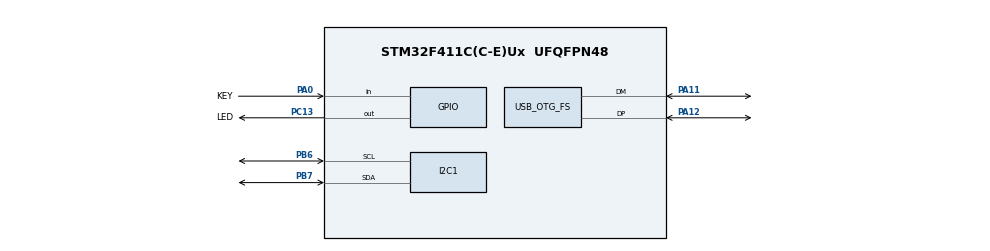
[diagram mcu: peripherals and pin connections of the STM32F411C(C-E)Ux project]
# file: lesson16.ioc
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Mcu.Family=STM32F4
Mcu.Name=STM32F411C(C-E)Ux
Mcu.Package=UFQFPN48
NVIC.OTG_FS_IRQn=true\:0\:0\:false\:false\:true\:false\:true\:true
NVIC.PriorityGroup=NVIC_PRIORITYGROUP_4
PA0-WKUP.GPIO_Label=KEY
PA0-WKUP.GPIO_PuPd=GPIO_PULLUP
PA0-WKUP.Signal=GPIO_Input
PA11.Mode=Device_Only
PA11.Signal=USB_OTG_FS_DM
PA12.Mode=Device_Only
PA12.Signal=USB_OTG_FS_DP
PA13.Mode=Serial_Wire
PA13.Signal=SYS_JTMS-SWDIO
PA14.Mode=Serial_Wire
PA14.Signal=SYS_JTCK-SWCLK
PB6.Mode=I2C
PB6.Signal=I2C1_SCL
PB7.Mode=I2C
PB7.Signal=I2C1_SDA
PC13-ANTI_TAMP.GPIO_Label=LED
PC13-ANTI_TAMP.PinState=GPIO_PIN_SET
PC13-ANTI_TAMP.Signal=GPIO_Output
PH0\ -\ OSC_IN.Mode=HSE-External-Oscillator
PH0\ -\ OSC_IN.Signal=RCC_OSC_IN
PH1\ -\ OSC_OUT.Mode=HSE-External-Oscillator
PH1\ -\ OSC_OUT.Signal=RCC_OSC_OUT
ProjectManager.HeapSize=0x200
ProjectManager.StackSize=0x1000
ProjectManager.TargetToolchain=CMake
RCC.48MHZClocksFreq_Value=48000000
RCC.AHBFreq_Value=96000000
RCC.APB1CLKDivider=RCC_HCLK_DIV2
RCC.APB1Freq_Value=48000000
RCC.APB1TimFreq_Value=96000000
RCC.APB2Freq_Value=96000000
RCC.APB2TimFreq_Value=96000000
RCC.CortexFreq_Value=96000000
RCC.HCLKFreq_Value=96000000
RCC.HSE_VALUE=25000000
RCC.HSI_VALUE=16000000
RCC.LSE_VALUE=32768
RCC.PLLM=25
RCC.SYSCLKFreq_VALUE=96000000
RCC.SYSCLKSource=RCC_SYSCLKSOURCE_PLLCLK
RCC.VCOOutputFreq_Value=192000000
USB_DEVICE.CLASS_NAME_FS=CDC
USB_DEVICE.VirtualMode=Cdc
USB_DEVICE.VirtualModeFS=Cdc_FS
USB_OTG_FS.VirtualMode=Device_Only
VP_USB_DEVICE_VS_USB_DEVICE_CDC_FS.Mode=CDC_FS
board=custom

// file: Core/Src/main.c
/* USER CODE BEGIN Header */
/**
  ******************************************************************************
  * @file           : main.c
  * @brief          : Main program body
  ******************************************************************************
  * @attention
  *
  * Copyright (c) 2026 STMicroelectronics.
  * All rights reserved.
  *
  * This software is licensed under terms that can be found in the LICENSE file
  * in the root directory of this software component.
  * If no LICENSE file comes with this software, it is provided AS-IS.
  *
  ******************************************************************************
  */
/* USER CODE END Header */
#include "main.h"
#include "usb_device.h"

/* USER CODE BEGIN Includes */
#include "app.h"
/* USER CODE END Includes */

I2C_HandleTypeDef hi2c1;

void SystemClock_Config(void);
static void MX_GPIO_Init(void);
static void MX_I2C1_Init(void);

int main(void)
{

  /* MCU Configuration--------------------------------------------------------*/

  /* Reset of all peripherals, Initializes the Flash interface and the Systick. */
  HAL_Init();

  /* Configure the system clock */
  SystemClock_Config();

  /* Initialize all configured peripherals */
  MX_GPIO_Init();
  MX_I2C1_Init();
  MX_USB_DEVICE_Init();
  /* USER CODE BEGIN 2 */
  app_init();
  /* USER CODE END 2 */

  /* Infinite loop */
  while (1)
  {

    /* USER CODE BEGIN 3 */
    app_loop();
  }
  /* USER CODE END 3 */
}

void SystemClock_Config(void)
{
  RCC_OscInitTypeDef RCC_OscInitStruct = {0};
  RCC_ClkInitTypeDef RCC_ClkInitStruct = {0};

  /** Configure the main internal regulator output voltage
  */
  __HAL_RCC_PWR_CLK_ENABLE();
  __HAL_PWR_VOLTAGESCALING_CONFIG(PWR_REGULATOR_VOLTAGE_SCALE1);

  /** Initializes the RCC Oscillators according to the specified parameters
  * in the RCC_OscInitTypeDef structure.
  */
  RCC_OscInitStruct.OscillatorType = RCC_OSCILLATORTYPE_HSE;
  RCC_OscInitStruct.HSEState = RCC_HSE_ON;
  RCC_OscInitStruct.PLL.PLLState = RCC_PLL_ON;
  RCC_OscInitStruct.PLL.PLLSource = RCC_PLLSOURCE_HSE;
  RCC_OscInitStruct.PLL.PLLM = 25;
  RCC_OscInitStruct.PLL.PLLN = 336;           /* F401: 84 MHz max */
  RCC_OscInitStruct.PLL.PLLP = RCC_PLLP_DIV4; /* 84 MHz SYSCLK */
  RCC_OscInitStruct.PLL.PLLQ = 7;             /* 48 MHz USB */
  if (HAL_RCC_OscConfig(&RCC_OscInitStruct) != HAL_OK)
  {
    Error_Handler();
  }

  /** Initializes the CPU, AHB and APB buses clocks
  */
  RCC_ClkInitStruct.ClockType = RCC_CLOCKTYPE_HCLK|RCC_CLOCKTYPE_SYSCLK
                              |RCC_CLOCKTYPE_PCLK1|RCC_CLOCKTYPE_PCLK2;
  RCC_ClkInitStruct.SYSCLKSource = RCC_SYSCLKSOURCE_PLLCLK;
  RCC_ClkInitStruct.AHBCLKDivider = RCC_SYSCLK_DIV1;
  RCC_ClkInitStruct.APB1CLKDivider = RCC_HCLK_DIV2;
  RCC_ClkInitStruct.APB2CLKDivider = RCC_HCLK_DIV1;

  if (HAL_RCC_ClockConfig(&RCC_ClkInitStruct, FLASH_LATENCY_3) != HAL_OK)
  {
    Error_Handler();
  }
}

static void MX_I2C1_Init(void)
{

  hi2c1.Instance = I2C1;
  hi2c1.Init.ClockSpeed = 100000;
  hi2c1.Init.DutyCycle = I2C_DUTYCYCLE_2;
  hi2c1.Init.OwnAddress1 = 0;
  hi2c1.Init.AddressingMode = I2C_ADDRESSINGMODE_7BIT;
  hi2c1.Init.DualAddressMode = I2C_DUALADDRESS_DISABLE;
  hi2c1.Init.OwnAddress2 = 0;
  hi2c1.Init.GeneralCallMode = I2C_GENERALCALL_DISABLE;
  hi2c1.Init.NoStretchMode = I2C_NOSTRETCH_DISABLE;
  if (HAL_I2C_Init(&hi2c1) != HAL_OK)
  {
    Error_Handler();
  }

}

static void MX_GPIO_Init(void)
{
  GPIO_InitTypeDef GPIO_InitStruct = {0};

  /* GPIO Ports Clock Enable */
  __HAL_RCC_GPIOC_CLK_ENABLE();
  __HAL_RCC_GPIOH_CLK_ENABLE();
  __HAL_RCC_GPIOA_CLK_ENABLE();
  __HAL_RCC_GPIOB_CLK_ENABLE();

  /*Configure GPIO pin Output Level */
  HAL_GPIO_WritePin(LED_GPIO_Port, LED_Pin, GPIO_PIN_SET);

  /*Configure GPIO pin : LED_Pin */
  GPIO_InitStruct.Pin = LED_Pin;
  GPIO_InitStruct.Mode = GPIO_MODE_OUTPUT_PP;
  GPIO_InitStruct.Pull = GPIO_NOPULL;
  GPIO_InitStruct.Speed = GPIO_SPEED_FREQ_LOW;
  HAL_GPIO_Init(LED_GPIO_Port, &GPIO_InitStruct);

  /*Configure GPIO pin : KEY_Pin */
  GPIO_InitStruct.Pin = KEY_Pin;
  GPIO_InitStruct.Mode = GPIO_MODE_INPUT;
  GPIO_InitStruct.Pull = GPIO_PULLUP;
  HAL_GPIO_Init(KEY_GPIO_Port, &GPIO_InitStruct);

}

void Error_Handler(void)
{
  __disable_irq();
  while (1)
  {
  }
}
